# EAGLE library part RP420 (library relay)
RELAY 2 x switch, Schrack

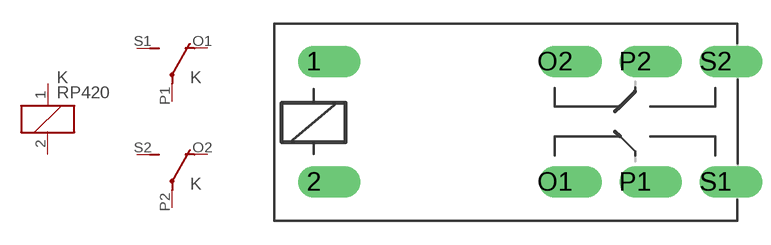
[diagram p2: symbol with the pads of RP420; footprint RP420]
Designator prefix K; gates 1=K 2=U 3=U

## RP420  [RP420]
1  1:1  pas
2  1:2  pas
O1  2:O  pas
O2  3:O  pas
P1  2:P  pas
P2  3:P  pas
S1  2:S  pas
S2  3:S  pas

## Footprint RP420 (pad centres in mm)
RELAY 2 x switch, Schrack
drill 1.321 offset: 1 -3.81,3.81; 2 -3.81,-3.81; O1 11.43,-3.81; O2 11.43,3.81; P1 16.51,-3.81; P2 16.51,3.81; S1 21.59,-3.81; S2 21.59,3.81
